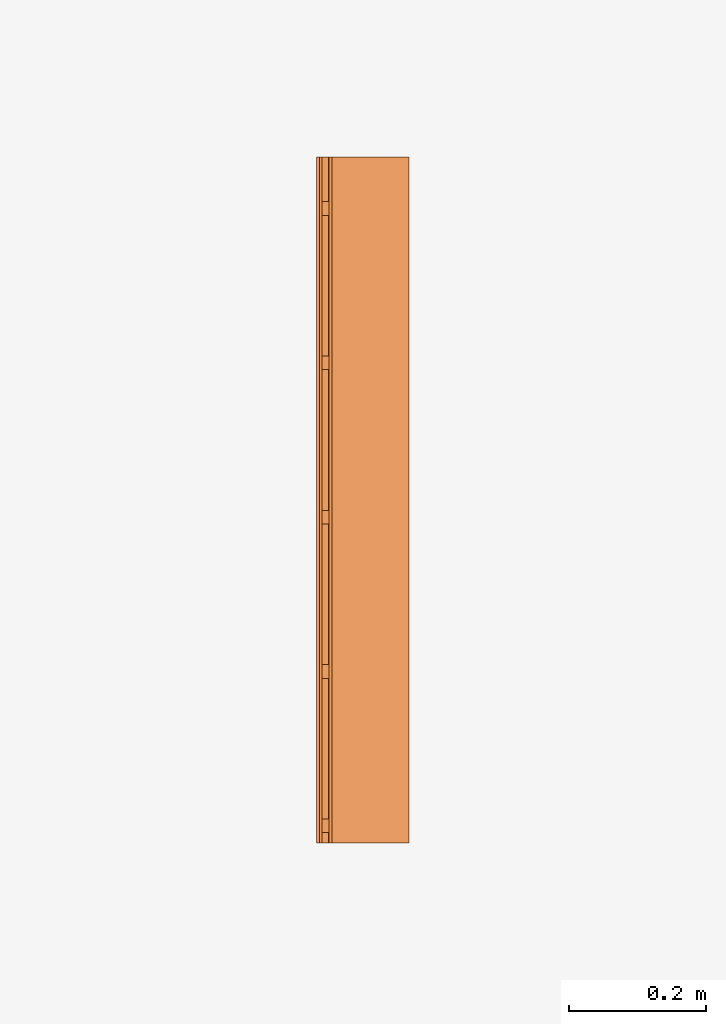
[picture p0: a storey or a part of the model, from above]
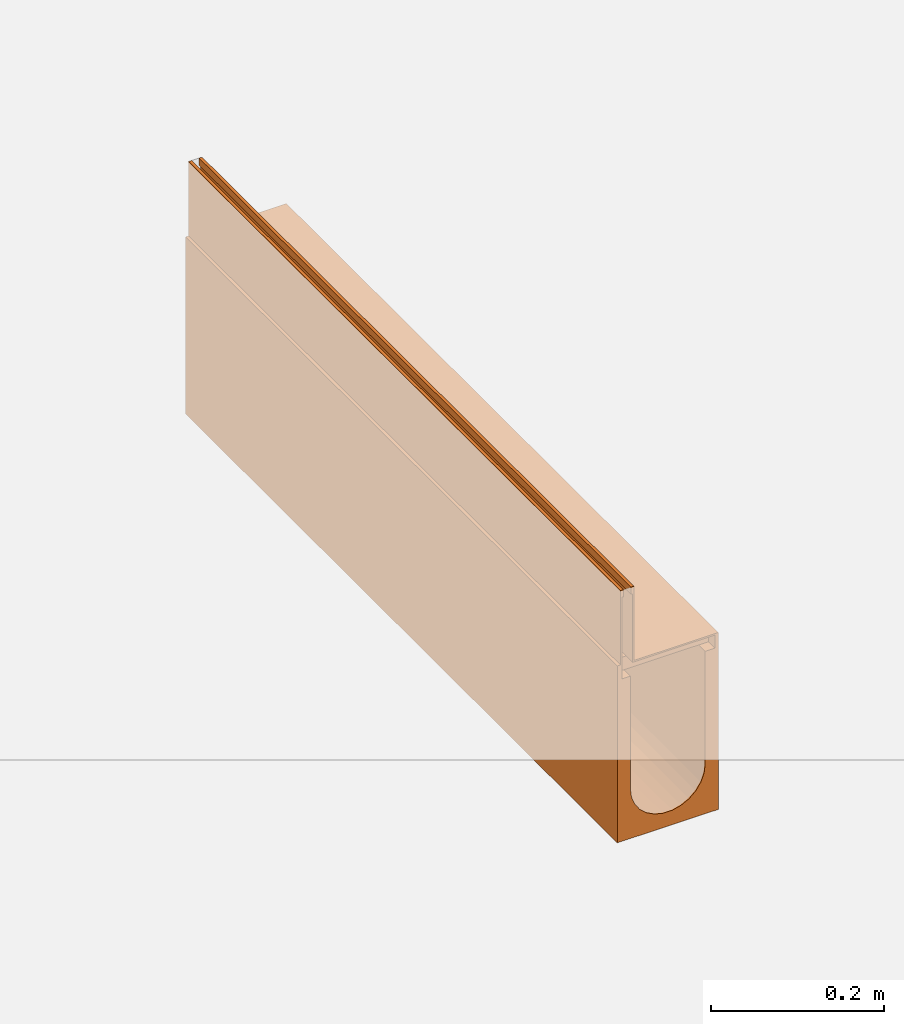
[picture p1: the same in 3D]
Properties of the parts of a building model (IFC2X3)

# File
Description: ViewDefinition [CoordinationView]
File name: 24200.ifc
Time: 2013-10-30T12:03:29
Written by: Autodesk Revit 2013
Made in: 20120221_2030(x64)

# IfcProject, Project Number
LongName: Project Name; Phase: Project Status

# IfcSite, Default
RefLatitude: 42, 21, 30, 344238; RefLongitude: -71, -3, -35, -194702; RefElevation: 0 mm

# IfcBuilding
Pset_BuildingCommon - NumberOfStoreys: 1
Other - Client Name: Owner; Project Address: ## Street City, State Zip; Project Issue Date: Issue Date; Project Name: Project Name; Project Number: Project Number; Project Status: Project Status

# IfcBuildingStorey, Level 1
LongName: Level 1; Elevation: 0 mm
Constraints - Elevation Base: 0; Elevation: 0 mm
Graphics - Symbol at End 2 Default: yes; Line Weight: 1; Symbol: M_Level Head - Circle: M_Level Head - Circle; Symbol at End 1 Default: no; Color: 0; Line Pattern: Center
Identity Data - Building Story: yes; Structural: no; Name: Level 1
Dimensions - Computation Height: 0 mm

# IfcBuildingElementProxy: 24200 - No 20.0 Constant Depth Channel - 1000mm LG - Invert Depth 230mm, Civil-Drainage-Channel-ACO-MultiDrain-M100DS-Brickslot-Channel-System:24200 - No 20.0 Constant Depth Channel - 1000mm LG - Invert Depth 230mm:24200 - No 20.0 Constant Depth Channel - 1000mm LG - Invert Depth 230mm:196059
In: Level 1
Material: Vienite® Synthetic Resin Concrete, Stainless Steel (F)
Dimensions - Length: 1000 mm; Custom_Void_length: 0 mm; Volume: 12087851 mm3; Brickslot Access Unit Void Bottom Depth: -6605 mm; FloorCut_Length: -1000 mm; Brickslot Access Unit Void Depth: -6500 mm; Brickslot Void Length: 1000 mm; Brickslot Void Depth: 0 mm; EndCap Position: 1000 mm; Depth: 250 mm; ShallowOverallDepth: 75 mm; Floor Cut Gap: 105 mm; ShallowInvDepth: 55 mm; GratingLength: -1000 mm; Length Drain: -1000 mm; Brickslot Access Unit Floor Cut Length: 500 mm; EndCap_Height: 250 mm; FloorCut_Width: 135 mm; InvDepth: 180 mm; FloorCut_Depth: 250 mm
Construction - 23476_Load Class C250 & D400_Brickslot Grating_Stainless Steel_500mm Long: no; 23404_Universal Endcap (Male End): no; 23475_Load Class C250 & D400_Brickslot Grating_Stainless Steel_1000mm Long: yes; 23477_Load Class C250 & D400_Brickslot_Access Unit_Stainless Steel_500mm Long: no; 23404_Universal Endcap (Female End): no; 23410_Sump Unit: no; Shallow Depth Channel with seal: no; Constant Depth Junction Channel: no; Constant Depth Channel: yes; Shallow Depth Channel: no
Constraints - Level: Level: Level 1; Moves With Nearby Elements: no
Phasing - Phase Created: New Construction
Pset_BuildingElementProxyCommon - Reference: 24200 - No 20.0 Constant Depth Channel - 1000mm LG - Invert Depth 230mm
General - TagNumber: 0; SerialNumber: 0
Identity Data - Price: POA - contact ACO; Product Page URL: http://www.aco.co.uk/product_detail.php?id=58; e-mail Sales: customersupport@aco.co.uk; Address: ACO Business Park, Hitchin Road, Shefford, Bedfordshire, United Kingdom SG17 5TE; Assembly Code: D2040; Watermarked With: BIM Manager Premium Suite; e-mail Technical: technical@aco.co.uk; URL: www.aco.co.uk; Watermarked By: www.aco.co.uk; Model Description: Channel drainage system; Type Comments: ACO MultiDrain M100DS 20.0 Constant Depth Channel 1000mm Long; Watermark 2: This file is water marked and users are prohibited to reproduce, adapt, distribute this information; Installation guidelines: http://www.aco.co.uk/download.php?id=173; Maintenance guidelines: http://www.aco.co.uk/download.php?id=173; Model: ACO MultiDrain MDS Brickslot- M100DS; Watermark 1: This file is the property of ACO Technologies PLC; Product Code: 24200; Telephone: +44 (0)1462 816666; Product brochure: http://www.aco.co.uk/download.php?id=173; OmniClass Title: Rainwater Removal; Cost: 0; OmniClass Number: 23.70.50.24; Manufacturer: ACO Technologies plc - ACO Water Management Division; Assembly Description: Rain Water Drainage; Fax: +44 (0)1462 815895
Model Properties - Brickslot Access Unit Product code 23477: Load Class C250/D400 - Brickslot Access Unit Stainless Steel - 500mm long x 105mm high -10mm Slot- Intake area - 1000mm²/m - 6.4 Kg; Brickslot Grating Product code 23476: Load Class C250/D400 - Brickslot Stainless Steel - 500mm long x 105mm high -10mm Slot- Intake area - 1000mm²/m - 3.3 Kg; Brickslot Grating Product code 23475: Load Class C250/D400 - Brickslot Stainless Steel - 1000mm long x 105mm high -10mm Slot- Intake area - 1000mm²/m - 6.6 Kg; End Cap Product code 23404: No 306 Universl End Cap - 135mm wide x 300mm long - Spigot Ø110mm x 50mm long - Silver - Polypropylene - 0.16kg
Data - Concrete Surround Volume - Load Class D 400 - Concrete Pavement: 0.21m³/m; Channel C.S.A: 0.017m²; Product Standard: BS EN 1433:2002, CE marked; Product Weight: 21.0 Kg; Invert Depth: 230mm; ACO Hydraulic Design Software: http://www.acodesign.co.uk; Installation - Concrete Grade: Refer to brochure; Pre-formed Outlet Ø: N/A; Hydraulic Performance: http://www.aco.co.uk/download.php?id=173; Product Dimensions: 1000mm x 135mm x 250mm (LxWxH); Concrete Surround Volume - Load Class A 15 - Concrete Pavement: 0.09m³/m; Load Class: A 15 - D 400; Concrete Surround Volume - Load Class B 125 - C 250 - Concrete Pavement: 0.14m³/m
Green Building Properties - Edge Rail Recyclable: Fully recyclable; Edge Rail Recycled Material Content: Between 40% - 90%; Channel Recyclable: Fully recyclable; Channel Recycled Material Content: 20% minimum
Other - Created By: www.aco.co.uk; Revision: 1
Materials and Finishes - Edge Rail Colour: Self; Edge Rail Material: Stainless Steel Grade 304; Channel Material: Vienite® Synthetic Resin Concrete; Channel Colour: Brown

# IfcOpeningElement: Recess (2)
In: Level 1
Dimensions - Volume: 9964360000 mm3; Thickness: 400 mm; Area: 25000000 mm2; Perimeter: 20000 mm
Structural - Enable Analytical Model: no; Structural: no
Constraints - Height Offset From Level: 0 mm; Level: Level: Level 1; Related to Mass: no; Room Bounding: yes
Phasing - Phase Created: New Construction
Construction - Function: 0; Default Thickness: 400 mm
Materials and Finishes - Structural Material: Earth
Graphics - Coarse Scale Fill Color: 0
Analytical Properties - Thermal Resistance (R): 0.477897; Roughness: 1; Heat Transfer Coefficient (U): 2.0925; Thermal mass: 543920; Absorptance: 0.1

# IfcSlab: Floor:Generic Floor - 400mm, Floor:Generic Floor - 400mm:193825
In: Level 1
PredefinedType: FLOOR; Material: Earth 400 mm
Dimensions - Volume: 9964360000 mm3; Thickness: 400 mm; Area: 25000000 mm2; Perimeter: 20000 mm
Structural - Enable Analytical Model: no; Structural: no
Constraints - Height Offset From Level: 0 mm; Level: Level: Level 1; Related to Mass: no; Room Bounding: yes
Phasing - Phase Created: New Construction
Pset_SlabCommon - Reference: Generic Floor - 400mm; IsExternal: no; LoadBearing: yes
Construction - Function: 0; Default Thickness: 400 mm
Materials and Finishes - Structural Material: Earth
Graphics - Coarse Scale Fill Color: 0
Analytical Properties - Thermal Resistance (R): 0.477897; Roughness: 1; Heat Transfer Coefficient (U): 2.0925; Thermal mass: 543920; Absorptance: 0.1
